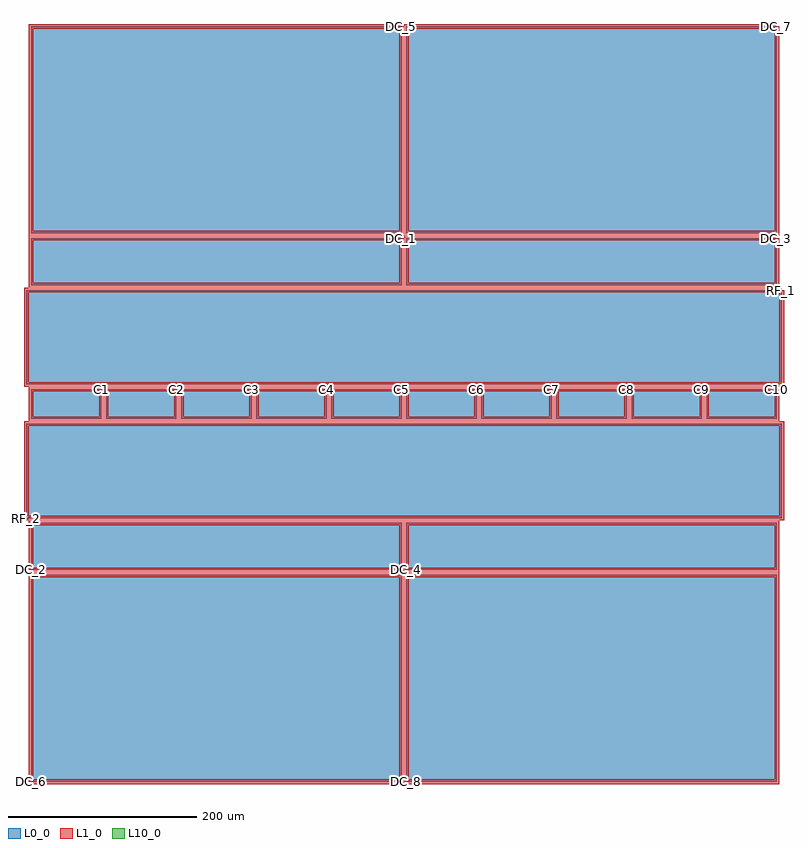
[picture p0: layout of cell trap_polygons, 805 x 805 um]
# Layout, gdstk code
import gdstk
lib = gdstk.Library(unit=1e-6, precision=1e-09)
def P(c, l, *ps):  # polygons
    for p in ps: c.add(gdstk.Polygon(p, *l))
L0_0 = (0, 0)
L1_0 = (1, 0)
L10_0 = (10, 0)

trap_polygons = lib.new_cell('trap_polygons')
P(trap_polygons, L0_0, [(2.5,-400),(2.5,-180.75),(395,-180.75),(395,-400),(2.5,-400)],
  [(395,400),(395,180.75),(2.5,180.75),(2.5,400),(395,400)],
  [(-395,-400),(-395,-180.75),(-2.5,-180.75),(-2.5,-400),(-395,-400)],
  [(-2.5,400),(-2.5,180.75),(-395,180.75),(-395,400),(-2.5,400)],
  [(2.5,-175.75),(2.5,-125.75),(395,-125.75),(395,-175.75),(2.5,-175.75)],
  [(395,175.75),(395,125.75),(2.5,125.75),(2.5,175.75),(395,175.75)],
  [(-395,-175.75),(-395,-125.75),(-2.5,-125.75),(-2.5,-175.75),(-395,-175.75)],
  [(-2.5,175.75),(-2.5,125.75),(-395,125.75),(-395,175.75),(-2.5,175.75)],
  [(395,15.75),(395,-15.75),(320.5,-15.75),(320.5,15.75),(395,15.75)],
  [(315.5,15.75),(315.5,-15.75),(241,-15.75),(241,15.75),(315.5,15.75)],
  [(236,15.75),(236,-15.75),(161.5,-15.75),(161.5,15.75),(236,15.75)],
  [(156.5,15.75),(156.5,-15.75),(82,-15.75),(82,15.75),(156.5,15.75)],
  [(77,15.75),(77,-15.75),(2.5,-15.75),(2.5,15.75),(77,15.75)],
  [(-2.5,15.75),(-2.5,-15.75),(-77,-15.75),(-77,15.75),(-2.5,15.75)],
  [(-82,15.75),(-82,-15.75),(-156.5,-15.75),(-156.5,15.75),(-82,15.75)],
  [(-161.5,15.75),(-161.5,-15.75),(-236,-15.75),(-236,15.75),(-161.5,15.75)],
  [(-241,15.75),(-241,-15.75),(-315.5,-15.75),(-315.5,15.75),(-241,15.75)],
  [(-320.5,15.75),(-320.5,-15.75),(-395,-15.75),(-395,15.75),(-320.5,15.75)],
  [(-400,-120.75),(-400,-20.75),(400,-20.75),(400,-120.75),(-400,-120.75)],
  [(400,120.75),(400,20.75),(-400,20.75),(-400,120.75),(400,120.75)])
P(trap_polygons, L1_0, [(0,-400),(5,-400),(5,-183.25),(392.5,-183.25),(392.5,-397.5),(2.5,-397.5),(2.5,-402.5),(397.5,-402.5),(397.5,-178.25),(0,-178.25)],
  [(397.5,400),(392.5,400),(392.5,183.25),(5,183.25),(5,397.5),(395,397.5),(395,402.5),(0,402.5),(0,178.25),(397.5,178.25)],
  [(-397.5,-400),(-392.5,-400),(-392.5,-183.25),(-5,-183.25),(-5,-397.5),(-395,-397.5),(-395,-402.5),(0,-402.5),(0,-178.25),(-397.5,-178.25)],
  [(0,400),(-5,400),(-5,183.25),(-392.5,183.25),(-392.5,397.5),(-2.5,397.5),(-2.5,402.5),(-397.5,402.5),(-397.5,178.25),(0,178.25)],
  [(0,-175.75),(5,-175.75),(5,-128.25),(392.5,-128.25),(392.5,-173.25),(2.5,-173.25),(2.5,-178.25),(397.5,-178.25),(397.5,-123.25),(0,-123.25)],
  [(397.5,175.75),(392.5,175.75),(392.5,128.25),(5,128.25),(5,173.25),(395,173.25),(395,178.25),(0,178.25),(0,123.25),(397.5,123.25)],
  [(-397.5,-175.75),(-392.5,-175.75),(-392.5,-128.25),(-5,-128.25),(-5,-173.25),(-395,-173.25),(-395,-178.25),(0,-178.25),(0,-123.25),(-397.5,-123.25)],
  [(0,175.75),(-5,175.75),(-5,128.25),(-392.5,128.25),(-392.5,173.25),(-2.5,173.25),(-2.5,178.25),(-397.5,178.25),(-397.5,123.25),(0,123.25)],
  [(397.5,15.75),(392.5,15.75),(392.5,-13.25),(323,-13.25),(323,13.25),(395,13.25),(395,18.25),(318,18.25),(318,-18.25),(397.5,-18.25)],
  [(318,15.75),(313,15.75),(313,-13.25),(243.5,-13.25),(243.5,13.25),(315.5,13.25),(315.5,18.25),(238.5,18.25),(238.5,-18.25),(318,-18.25)],
  [(238.5,15.75),(233.5,15.75),(233.5,-13.25),(164,-13.25),(164,13.25),(236,13.25),(236,18.25),(159,18.25),(159,-18.25),(238.5,-18.25)],
  [(159,15.75),(154,15.75),(154,-13.25),(84.5,-13.25),(84.5,13.25),(156.5,13.25),(156.5,18.25),(79.5,18.25),(79.5,-18.25),(159,-18.25)],
  [(79.5,15.75),(74.5,15.75),(74.5,-13.25),(5,-13.25),(5,13.25),(77,13.25),(77,18.25),(0,18.25),(0,-18.25),(79.5,-18.25)],
  [(0,15.75),(-5,15.75),(-5,-13.25),(-74.5,-13.25),(-74.5,13.25),(-2.5,13.25),(-2.5,18.25),(-79.5,18.25),(-79.5,-18.25),(0,-18.25)],
  [(-79.5,15.75),(-84.5,15.75),(-84.5,-13.25),(-154,-13.25),(-154,13.25),(-82,13.25),(-82,18.25),(-159,18.25),(-159,-18.25),(-79.5,-18.25)],
  [(-159,15.75),(-164,15.75),(-164,-13.25),(-233.5,-13.25),(-233.5,13.25),(-161.5,13.25),(-161.5,18.25),(-238.5,18.25),(-238.5,-18.25),(-159,-18.25)],
  [(-238.5,15.75),(-243.5,15.75),(-243.5,-13.25),(-313,-13.25),(-313,13.25),(-241,13.25),(-241,18.25),(-318,18.25),(-318,-18.25),(-238.5,-18.25)],
  [(-318,15.75),(-323,15.75),(-323,-13.25),(-392.5,-13.25),(-392.5,13.25),(-320.5,13.25),(-320.5,18.25),(-397.5,18.25),(-397.5,-18.25),(-318,-18.25)],
  [(-402.5,-120.75),(-397.5,-120.75),(-397.5,-23.25),(397.5,-23.25),(397.5,-118.25),(-400,-118.25),(-400,-123.25),(402.5,-123.25),(402.5,-18.25),(-402.5,-18.25)],
  [(402.5,120.75),(397.5,120.75),(397.5,23.25),(-397.5,23.25),(-397.5,118.25),(400,118.25),(400,123.25),(-402.5,123.25),(-402.5,18.25),(402.5,18.25)])
P(trap_polygons, L10_0, [(0,0),(0,0),(0,0),(0,0)])
trap_polygons.add(gdstk.Label('DC_8', (2.5,-400), layer=2, texttype=0))
trap_polygons.add(gdstk.Label('DC_7', (395,400), layer=2, texttype=0))
trap_polygons.add(gdstk.Label('DC_6', (-395,-400), layer=2, texttype=0))
trap_polygons.add(gdstk.Label('DC_5', (-2.5,400), layer=2, texttype=0))
trap_polygons.add(gdstk.Label('DC_4', (2.5,-175.75), layer=2, texttype=0))
trap_polygons.add(gdstk.Label('DC_3', (395,175.75), layer=2, texttype=0))
trap_polygons.add(gdstk.Label('DC_2', (-395,-175.75), layer=2, texttype=0))
trap_polygons.add(gdstk.Label('DC_1', (-2.5,175.75), layer=2, texttype=0))
trap_polygons.add(gdstk.Label('C10', (395,15.75), layer=2, texttype=0))
trap_polygons.add(gdstk.Label('C9', (315.5,15.75), layer=2, texttype=0))
trap_polygons.add(gdstk.Label('C8', (236,15.75), layer=2, texttype=0))
trap_polygons.add(gdstk.Label('C7', (156.5,15.75), layer=2, texttype=0))
trap_polygons.add(gdstk.Label('C6', (77,15.75), layer=2, texttype=0))
trap_polygons.add(gdstk.Label('C5', (-2.5,15.75), layer=2, texttype=0))
trap_polygons.add(gdstk.Label('C4', (-82,15.75), layer=2, texttype=0))
trap_polygons.add(gdstk.Label('C3', (-161.5,15.75), layer=2, texttype=0))
trap_polygons.add(gdstk.Label('C2', (-241,15.75), layer=2, texttype=0))
trap_polygons.add(gdstk.Label('C1', (-320.5,15.75), layer=2, texttype=0))
trap_polygons.add(gdstk.Label('RF_2', (-400,-120.75), layer=2, texttype=0))
trap_polygons.add(gdstk.Label('RF_1', (400,120.75), layer=2, texttype=0))

lib.write_gds('trap_polygons.gds')
